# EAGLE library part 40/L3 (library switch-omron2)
OMRON SWITCH

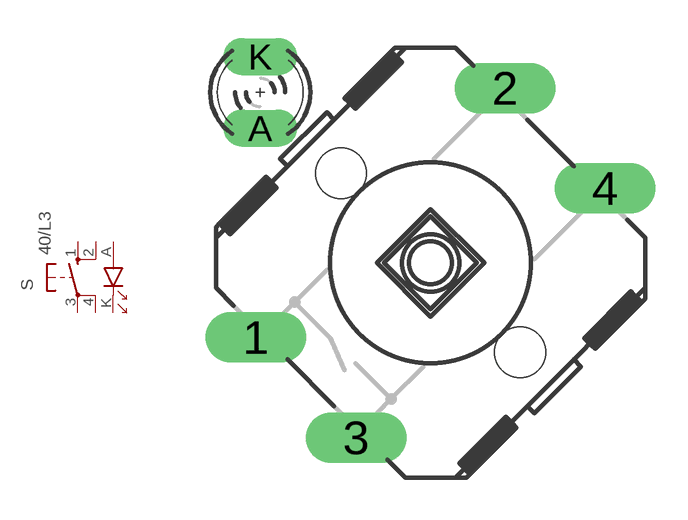
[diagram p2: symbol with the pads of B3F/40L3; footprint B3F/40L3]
Designator prefix S

## 40/L3 (OC_FARNELL: unknown; OC_NEWARK: unknown)  [B3F/40L3]
1  S  pas
2  S1  pas
3  P  pas
4  P1  pas
A  A  pas
K  C  pas

## Footprint B3F/40L3 (pad centres in mm)
OMRON SWITCH with LED 3mm
drill 1.194 long: 1 -6.198,-2.642; 2 2.642,6.198; 3 -2.642,-6.198; 4 6.198,2.642
drill 0.813 long: A -6.045,4.775; K -6.045,7.315
hole 1.803 at 3.175,-3.175
hole 1.803 at -3.175,3.175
